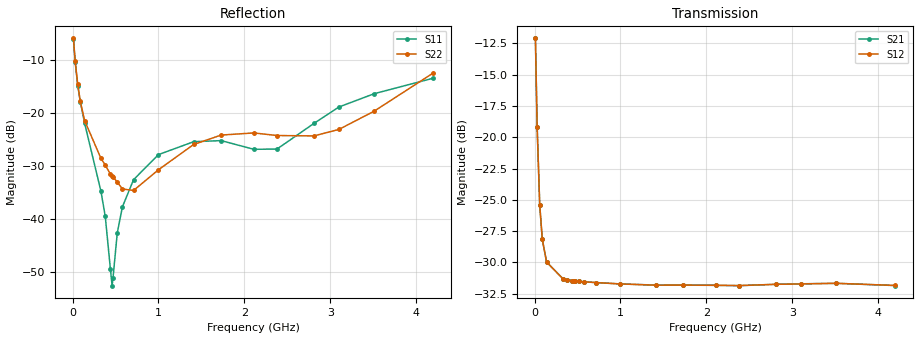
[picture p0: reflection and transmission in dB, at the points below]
! Integrated Device Technology
! Corporate Headquarters
! 6024 Silver Creek Valley Road
! San Jose, CA 95138  USA
! Phone:  1-408-284-8200
! Toll Free:  1-800-223-1366
! Webpage:  http://www.idt.com/
! Timing and RF Division
! 515 Groton Road, Suite 102
! Westford, MA 01886-6024
! Device:  F1950
! Description: 7-bit 0.25 dB Digital Step Attenuator
! Frequency:  150.0 -  4000.00 MHz
! Package:  4x4 mm Thin QFN Plastic Package: 24 pin
! Ports:  2 RF, 12 DC
!  Pin  1  = D0
!  Pin  2  = VDD
!  Pin  3  = Vmode
!  Pin  4  = GND
!  Pin  5  = RF1  =  Port 1
!  Pin  6  = GND
!  Pin  7  = GND
!  Pin  8  = GND
!  Pin  9  = GND
!  Pin 10  = GND
!  Pin 11  = GND
!  Pin 12  = GND
!  Pin 13  = GND
!  Pin 14  = RF2  =  Port 2
!  Pin 15  = GND
!  Pin 16  = LE
!  Pin 17  = CLK
!  Pin 18  = DATE
!  Pin 19  = D6
!  Pin 20  = D5
!  Pin 21  = D4
!  Pin 22  = D3
!  Pin 23  = D2
!  Pin 24  = D1
! State:  123
! Atten State:  30.75 dB
! Voltage:  +5.00 Volts
! Current:  Not Measured mA
! Data:  The device was measured on a the F195X evaluation board which has
!  individual transmission lines to the RF pins.  Data was collected
!  using a calibrated network analyzer.  The evaluation board was
!  de-embedded using a TRL calibration technique.
!  The reference plane is the edge of the package pin.
! Misc:  Board 2019
!  Action Tracker AT0250
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# GHz S dB R 50
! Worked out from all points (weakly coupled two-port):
!   420 points, 10 MHz to 4.2 GHz, reference 50 ohm
!   highest |S21| = -12.09 dB at 10 MHz (marker M1); lowest = -31.9 dB at 2.38 GHz (marker M2)
!   lowest |S11| = -52.6 dB at 460 MHz (marker M3), VSWR 1.00, Z = 49.8 - j0.0933 ohm
!   |S11| at or under -10 dB: 28.27 MHz to end of sweep
!   |S22| runs from -35.0 to -5.9 dB; largest |S21 - S12| = 6.5e-05
!   S11 on the Smith chart (normalised r, x): 10 MHz: 2.05, -1.25; 30 MHz: 1.27, -0.67; 60 MHz: 1.10, -0.37; 330 MHz: 1.01, -0.04; 4.2 GHz: 0.68, +0.17
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0.01  -6.09 -27.7  -12.09 -40.2  -12.09 -40.1  -5.95 -28.6
0.03  -10.35 -51.9  -19.14 -65.9  -19.14 -65.9  -10.23 -53.5
0.06  -14.87 -64.6  -25.41 -61.0  -25.40 -61.0  -14.62 -66.2
0.09  -17.92 -70.2  -28.15 -49.8  -28.15 -49.8  -17.85 -70.6
0.14  -21.96 -73.0  -29.97 -36.6  -29.97 -36.6  -21.46 -75.0
0.33  -34.79 -73.9  -31.30 -19.0  -31.31 -19.0  -28.60 -85.3
0.38  -39.49 -75.0  -31.39 -17.2  -31.39 -17.3  -29.86 -87.6
0.44  -49.43 -108.2  -31.46 -15.8  -31.46 -15.8  -31.56 -93.3
0.46  -52.63 -156.4  -31.48 -15.4  -31.48 -15.4  -31.97 -96.6
0.47  -51.27 177.0  -31.49 -15.3  -31.48 -15.3  -32.11 -98.2
0.52  -42.71 144.7  -31.52 -14.5  -31.52 -14.6  -33.06 -103.1
0.58  -37.75 137.6  -31.55 -14.0  -31.55 -14.0  -34.37 -115.8
0.71  -32.62 139.1  -31.61 -13.2  -31.61 -13.2  -34.66 -140.9
1  -27.89 148.2  -31.72 -13.1  -31.72 -13.1  -30.75 178.5
1.41  -25.45 162.8  -31.81 -14.0  -31.82 -14.0  -25.97 160.0
1.73  -25.25 167.9  -31.82 -15.0  -31.81 -15.0  -24.20 151.6
2.11  -26.89 157.4  -31.83 -17.2  -31.83 -17.2  -23.80 141.6
2.38  -26.84 130.7  -31.86 -18.2  -31.85 -18.3  -24.29 132.8
2.81  -22.00 105.5  -31.75 -20.9  -31.75 -20.9  -24.36 115.3
3.1  -18.91 107.1  -31.71 -22.7  -31.72 -22.7  -23.14 110.5
3.51  -16.40 117.4  -31.67 -24.9  -31.67 -25.0  -19.70 112.8
4.2  -13.46 145.5  -31.85 -26.2  -31.84 -26.3  -12.47 126.9
